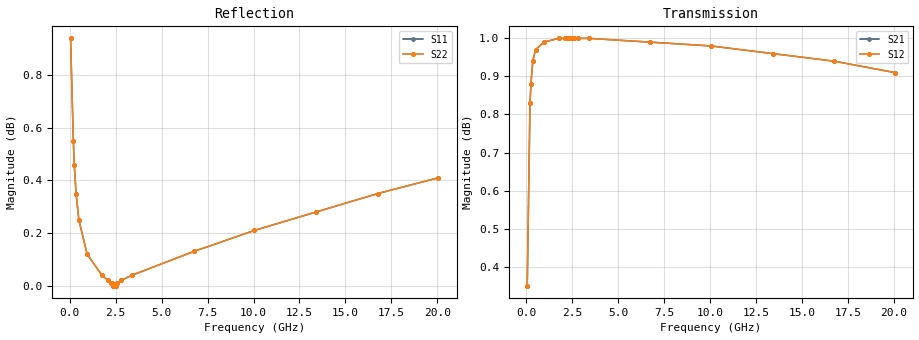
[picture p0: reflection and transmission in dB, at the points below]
! AVX Thin Film Operation		Date: may 2004
! Description: Accu-P® Series, Thin Film, SMD, RF Capacitor
! Part Number: 0201ZK120JBW
! 50 MHz  -  10.05 GHz
! Serial Measurements
# mhz S db R 50
!	S11		S21		S12		S22
!	dB	Phase	dB	Phase	dB	Phase	dB	Phase
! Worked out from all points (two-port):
!   401 points, 50 MHz to 20.05 GHz, reference 50 ohm
!   highest |S21| = 1.00 dB at 1.75 GHz (marker M1); lowest = 0.4 dB at 50 MHz (marker M2)
!   |S21| within 3 dB of the highest: start of sweep to end of sweep
!   lowest |S11| = 0.0 dB at 2.4 GHz (marker M3)
!   |S11| at or under -10 dB: nowhere
!   |S22| runs from 0.0 to 0.9 dB; largest |S21 - S12| = 0
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50  0.94 -20.7  0.35 69.3  0.35 69.3  0.94 -20.7
200  0.55 -56.5  0.83 33.3  0.83 33.3  0.55 -56.5
250  0.46 -62.2  0.88 27.7  0.88 27.7  0.46 -62.2
350  0.35 -69.4  0.94 20.3  0.94 20.3  0.35 -69.4
500  0.25 -75.4  0.97 14.2  0.97 14.2  0.25 -75.4
950  0.12 -82.5  0.99 6.7  0.99 6.7  0.12 -82.5
1750  0.04 -85.5  1.00 2.1  1.00 2.1  0.04 -85.5
2100  0.02 -83.5  1.00 0.9  1.00 0.9  0.02 -83.5
2250  0.01 -78.6  1.00 0.5  1.00 0.5  0.01 -78.6
2300  0.01 -74.3  1.00 0.3  1.00 0.3  0.01 -74.3
2350  0.00 -64.5  1.00 0.2  1.00 0.2  0.00 -64.5
2400  0.00 -32.1  1.00 0.1  1.00 0.1  0.00 -32.1
2500  0.00 65.9  1.00 -0.2  1.00 -0.2  0.00 65.9
2550  0.01 74.4  1.00 -0.3  1.00 -0.3  0.01 74.4
2600  0.01 78.3  1.00 -0.4  1.00 -0.4  0.01 78.3
2800  0.02 83.5  1.00 -0.9  1.00 -0.9  0.02 83.5
3400  0.04 85.5  1.00 -2.2  1.00 -2.2  0.04 85.5
6750  0.13 81.8  0.99 -7.6  0.99 -7.6  0.13 81.8
10050  0.21 77.5  0.98 -12.1  0.98 -12.1  0.21 77.5
13400  0.28 73.4  0.96 -16.3  0.96 -16.3  0.28 73.4
16750  0.35 69.4  0.94 -20.3  0.94 -20.3  0.35 69.4
20050  0.41 65.8  0.91 -24.0  0.91 -24.0  0.41 65.8
